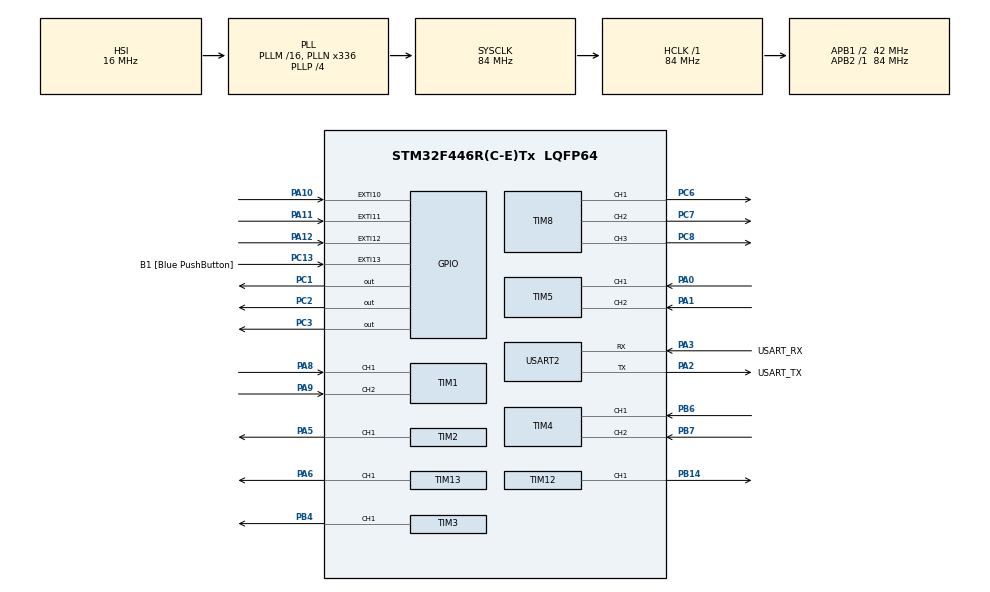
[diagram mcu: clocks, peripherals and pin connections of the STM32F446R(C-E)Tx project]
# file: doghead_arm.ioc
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Dma.Request0=USART2_RX
Dma.Request1=USART2_TX
Dma.USART2_RX.0.Direction=DMA_PERIPH_TO_MEMORY
Dma.USART2_RX.0.FIFOMode=DMA_FIFOMODE_DISABLE
Dma.USART2_RX.0.Instance=DMA1_Stream5
Dma.USART2_RX.0.MemDataAlignment=DMA_MDATAALIGN_BYTE
Dma.USART2_RX.0.MemInc=DMA_MINC_ENABLE
Dma.USART2_RX.0.Mode=DMA_CIRCULAR
Dma.USART2_RX.0.PeriphDataAlignment=DMA_PDATAALIGN_BYTE
Dma.USART2_RX.0.PeriphInc=DMA_PINC_DISABLE
Dma.USART2_RX.0.Priority=DMA_PRIORITY_VERY_HIGH
Dma.USART2_TX.1.Direction=DMA_MEMORY_TO_PERIPH
Dma.USART2_TX.1.FIFOMode=DMA_FIFOMODE_DISABLE
Dma.USART2_TX.1.Instance=DMA1_Stream6
Dma.USART2_TX.1.MemDataAlignment=DMA_MDATAALIGN_BYTE
Dma.USART2_TX.1.MemInc=DMA_MINC_ENABLE
Dma.USART2_TX.1.Mode=DMA_NORMAL
Dma.USART2_TX.1.PeriphDataAlignment=DMA_PDATAALIGN_BYTE
Dma.USART2_TX.1.PeriphInc=DMA_PINC_DISABLE
Dma.USART2_TX.1.Priority=DMA_PRIORITY_VERY_HIGH
FREERTOS.Tasks01=CommTask,24,3072,StartCommTask,Default,NULL,Dynamic,NULL,NULL;ControlTask,32,1024,StartControlTask,Default,NULL,Dynamic,NULL,NULL
FREERTOS.configTOTAL_HEAP_SIZE=49152
FREERTOS.configUSE_NEWLIB_REENTRANT=1
Mcu.Family=STM32F4
Mcu.Name=STM32F446R(C-E)Tx
Mcu.Package=LQFP64
NVIC.DMA1_Stream5_IRQn=true\:6\:0\:true\:false\:true\:true\:false\:true\:true
NVIC.DMA1_Stream6_IRQn=true\:6\:0\:true\:false\:true\:true\:false\:true\:true
NVIC.EXTI15_10_IRQn=true\:5\:0\:false\:false\:true\:true\:true\:true\:true
NVIC.PriorityGroup=NVIC_PRIORITYGROUP_4
NVIC.TIM6_DAC_IRQn=true\:5\:0\:true\:false\:true\:true\:true\:true\:true
NVIC.TIM7_IRQn=true\:15\:0\:false\:false\:true\:false\:false\:true\:true
NVIC.TimeBase=TIM7_IRQn
NVIC.TimeBaseIP=TIM7
NVIC.USART2_IRQn=true\:6\:0\:true\:false\:true\:true\:true\:true\:true
PA0-WKUP.GPIO_PuPd=GPIO_PULLUP
PA0-WKUP.Signal=S_TIM5_CH1
PA1.GPIO_PuPd=GPIO_PULLUP
PA1.Signal=S_TIM5_CH2
PA10.GPIO_ModeDefaultEXTI=GPIO_MODE_IT_RISING_FALLING
PA10.GPIO_PuPd=GPIO_PULLUP
PA10.Signal=GPXTI10
PA11.GPIO_ModeDefaultEXTI=GPIO_MODE_IT_RISING_FALLING
PA11.GPIO_PuPd=GPIO_PULLUP
PA11.Signal=GPXTI11
PA12.GPIO_ModeDefaultEXTI=GPIO_MODE_IT_RISING_FALLING
PA12.GPIO_PuPd=GPIO_PULLUP
PA12.Signal=GPXTI12
PA13.GPIO_Label=TMS
PA13.Mode=Serial_Wire
PA13.Signal=SYS_JTMS-SWDIO
PA14.GPIO_Label=TCK
PA14.Mode=Serial_Wire
PA14.Signal=SYS_JTCK-SWCLK
PA2.GPIO_Label=USART_TX
PA2.Mode=Asynchronous
PA2.Signal=USART2_TX
PA3.GPIO_Label=USART_RX
PA3.Mode=Asynchronous
PA3.Signal=USART2_RX
PA5.Signal=S_TIM2_CH1_ETR
PA6.Signal=S_TIM13_CH1
PA8.GPIO_PuPd=GPIO_PULLUP
PA8.Signal=S_TIM1_CH1
PA9.GPIO_PuPd=GPIO_PULLUP
PA9.Signal=S_TIM1_CH2
PB14.Signal=S_TIM12_CH1
PB3.GPIO_Label=SWO
PB3.Signal=SYS_JTDO-SWO
PB4.Signal=S_TIM3_CH1
PB6.GPIO_PuPd=GPIO_PULLUP
PB6.Signal=S_TIM4_CH1
PB7.GPIO_PuPd=GPIO_PULLUP
PB7.Signal=S_TIM4_CH2
PC1.Signal=GPIO_Output
PC13.GPIO_Label=B1 [Blue PushButton]
PC13.GPIO_ModeDefaultEXTI=GPIO_MODE_IT_FALLING
PC13.Signal=GPXTI13
PC14-OSC32_IN.Mode=LSE-External-Oscillator
PC14-OSC32_IN.Signal=RCC_OSC32_IN
PC15-OSC32_OUT.Mode=LSE-External-Oscillator
PC15-OSC32_OUT.Signal=RCC_OSC32_OUT
PC2.Signal=GPIO_Output
PC3.Signal=GPIO_Output
PC6.Signal=S_TIM8_CH1
PC7.Signal=S_TIM8_CH2
PC8.Signal=S_TIM8_CH3
PH0-OSC_IN.Mode=HSE-External-Oscillator
PH0-OSC_IN.Signal=RCC_OSC_IN
PH1-OSC_OUT.Mode=HSE-External-Oscillator
PH1-OSC_OUT.Signal=RCC_OSC_OUT
ProjectManager.HeapSize=0x200
ProjectManager.StackSize=0x400
ProjectManager.TargetToolchain=STM32CubeIDE
RCC.48MHZClocksFreq_Value=84000000
RCC.AHBFreq_Value=84000000
RCC.APB1CLKDivider=RCC_HCLK_DIV2
RCC.APB1Freq_Value=42000000
RCC.APB1TimFreq_Value=84000000
RCC.APB2Freq_Value=84000000
RCC.APB2TimFreq_Value=84000000
RCC.CortexFreq_Value=84000000
RCC.FLatency-AdvancedSettings=FLASH_LATENCY_2
RCC.HCLKFreq_Value=84000000
RCC.HSE_VALUE=8000000
RCC.HSI_VALUE=16000000
RCC.PLLN=336
RCC.PLLP=RCC_PLLP_DIV4
RCC.SYSCLKFreq_VALUE=84000000
RCC.SYSCLKSource=RCC_SYSCLKSOURCE_PLLCLK
RCC.USBFreq_Value=168000000
RCC.VCOOutputFreq_Value=336000000
SH.S_TIM12_CH1.0=TIM12_CH1,PWM Generation1 CH1
SH.S_TIM13_CH1.0=TIM13_CH1,PWM Generation1 CH1
SH.S_TIM1_CH1.0=TIM1_CH1,Encoder_Interface
SH.S_TIM1_CH2.0=TIM1_CH2,Encoder_Interface
SH.S_TIM2_CH1_ETR.0=TIM2_CH1,PWM Generation1 CH1
SH.S_TIM3_CH1.0=TIM3_CH1,PWM Generation1 CH1
SH.S_TIM4_CH1.0=TIM4_CH1,Encoder_Interface
SH.S_TIM4_CH2.0=TIM4_CH2,Encoder_Interface
SH.S_TIM5_CH1.0=TIM5_CH1,Encoder_Interface
SH.S_TIM5_CH2.0=TIM5_CH2,Encoder_Interface
SH.S_TIM8_CH1.0=TIM8_CH1,PWM Generation1 CH1
SH.S_TIM8_CH2.0=TIM8_CH2,PWM Generation2 CH2
SH.S_TIM8_CH3.0=TIM8_CH3,PWM Generation3 CH3
TIM1.EncoderMode=TIM_ENCODERMODE_TI12
TIM1.IC1Filter=7
TIM1.IC2Filter=7
TIM12.Channel-PWM\ Generation1\ CH1=TIM_CHANNEL_1
TIM13.Channel=TIM_CHANNEL_1
TIM2.AutoReloadPreload=TIM_AUTORELOAD_PRELOAD_ENABLE
TIM2.Channel-PWM\ Generation1\ CH1=TIM_CHANNEL_1
TIM3.AutoReloadPreload=TIM_AUTORELOAD_PRELOAD_ENABLE
TIM3.Channel-PWM\ Generation1\ CH1=TIM_CHANNEL_1
TIM4.EncoderMode=TIM_ENCODERMODE_TI12
TIM4.IC1Filter=7
TIM4.IC2Filter=7
TIM5.EncoderMode=TIM_ENCODERMODE_TI12
TIM5.IC1Filter=7
TIM5.IC2Filter=7
TIM6.Period=999
TIM6.Prescaler=83
TIM8.Channel-PWM\ Generation1\ CH1=TIM_CHANNEL_1
TIM8.Channel-PWM\ Generation2\ CH2=TIM_CHANNEL_2
TIM8.Channel-PWM\ Generation3\ CH3=TIM_CHANNEL_3
USART2.VirtualMode=VM_ASYNC
VP_FREERTOS_VS_CMSIS_V2.Mode=CMSIS_V2
VP_SYS_VS_tim7.Mode=TIM7
VP_TIM13_VS_ClockSourceINT.Mode=Enable_Timer
VP_TIM6_VS_ClockSourceINT.Mode=Enable_Timer
board=NUCLEO-F446RE

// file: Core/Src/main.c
/* USER CODE BEGIN Header */
/**
  ******************************************************************************
  * @file           : main.c
  * @brief          : Main program body
  ******************************************************************************
  * @attention
  *
  * Copyright (c) 2025 STMicroelectronics.
  * All rights reserved.
  *
  * This software is licensed under terms that can be found in the LICENSE file
  * in the root directory of this software component.
  * If no LICENSE file comes with this software, it is provided AS-IS.
  *
  ******************************************************************************
  */
/* USER CODE END Header */
#include "main.h"
#include "cmsis_os.h"

/* USER CODE BEGIN Includes */
#include "mainpp.h"
#include "robot_config.h"
#include "hardware_io.h"
//#include <rcl/rcl.h>
//#include <rcl/error_handling.h>
//#include <rclc/rclc.h>
//#include <rclc/executor.h>
//#include <uxr/client/transport.h>
//#include <rmw_microxrcedds_c/config.h>
//#include <rmw_microros/rmw_microros.h>
/* USER CODE END Includes */

TIM_HandleTypeDef htim1;
TIM_HandleTypeDef htim2;
TIM_HandleTypeDef htim3;
TIM_HandleTypeDef htim4;
TIM_HandleTypeDef htim5;
TIM_HandleTypeDef htim6;
TIM_HandleTypeDef htim8;
TIM_HandleTypeDef htim12;
TIM_HandleTypeDef htim13;

UART_HandleTypeDef huart2;
DMA_HandleTypeDef hdma_usart2_rx;
DMA_HandleTypeDef hdma_usart2_tx;

/* Definitions for defaultTask */
osThreadId_t defaultTaskHandle;
const osThreadAttr_t defaultTask_attributes = {
  .name = "defaultTask",
  .stack_size = 512 * 4,
  .priority = (osPriority_t) osPriorityNormal,
};
/* USER CODE BEGIN PV */
// 所有的控制變數已經移動到 robot_arm_core.cpp 與 mainpp.h

// [Task Handle] 控制任務句柄（供 TIM6 中斷使用）
TaskHandle_t xControlTaskHandle = NULL;
/* USER CODE END PV */

void SystemClock_Config(void);
static void MX_GPIO_Init(void);
static void MX_DMA_Init(void);
static void MX_USART2_UART_Init(void);
static void MX_TIM1_Init(void);
static void MX_TIM2_Init(void);
static void MX_TIM3_Init(void);
static void MX_TIM4_Init(void);
static void MX_TIM6_Init(void);
static void MX_TIM5_Init(void);
static void MX_TIM8_Init(void);
static void MX_TIM12_Init(void);
static void MX_TIM13_Init(void);
void StartDefaultTask(void *argument);

/* USER CODE BEGIN PFP */
#include "nidec_motor_driver.h"
void MX_FREERTOS_Init(void);
/* USER CODE END PFP */

/* USER CODE BEGIN 0 */
#include "runtime_monitor.h"
/* USER CODE END 0 */

int main(void)
{

  /* MCU Configuration--------------------------------------------------------*/

  /* Reset of all peripherals, Initializes the Flash interface and the Systick. */
																																				  HAL_Init();

  /* Configure the system clock */
  SystemClock_Config();

  /* USER CODE BEGIN SysInit */
  RuntimeMonitor_Init();
  /* USER CODE END SysInit */

  /* Initialize all configured peripherals */
  MX_GPIO_Init();
  MX_DMA_Init();
  MX_USART2_UART_Init();
  MX_TIM1_Init();
  MX_TIM2_Init();
  MX_TIM3_Init();
  MX_TIM4_Init();
  MX_TIM6_Init();
  MX_TIM5_Init();
  MX_TIM8_Init();
  MX_TIM12_Init();
  MX_TIM13_Init();
  /* USER CODE BEGIN 2 */
    Robot_Init();
    // 模式切換統一使用 test_mode_selection 變數控制
  /* USER CODE END 2 */

  /* Init scheduler */
  osKernelInitialize();

  /* Create the thread(s) */
  /* creation of defaultTask */
  defaultTaskHandle = osThreadNew(StartDefaultTask, NULL, &defaultTask_attributes);
  if (defaultTaskHandle == NULL) {
    Error_Handler();
  }

  /* USER CODE BEGIN RTOS_THREADS */
  /* add threads, ... */
  MX_FREERTOS_Init();  // 建立自訂的控制任務和通訊任務
  /* USER CODE END RTOS_THREADS */

  /* Start scheduler */
  osKernelStart();

  /* We should never get here as control is now taken by the scheduler */

  /* Infinite loop */
  while (1)
  {

    /* USER CODE BEGIN 3 */
    // 注意: FreeRTOS 啟動後 (osKernelStart) 不會執行這裡
    // 所有控制邏輯應放在 FreeRTOS 任務中
  }
  /* USER CODE END 3 */
}

void SystemClock_Config(void)
{
  RCC_OscInitTypeDef RCC_OscInitStruct = {0};
  RCC_ClkInitTypeDef RCC_ClkInitStruct = {0};

  /** Configure the main internal regulator output voltage
  */
  __HAL_RCC_PWR_CLK_ENABLE();
  __HAL_PWR_VOLTAGESCALING_CONFIG(PWR_REGULATOR_VOLTAGE_SCALE3);

  /** Initializes the RCC Oscillators according to the specified parameters
  * in the RCC_OscInitTypeDef structure.
  */
  RCC_OscInitStruct.OscillatorType = RCC_OSCILLATORTYPE_HSI;
  RCC_OscInitStruct.HSIState = RCC_HSI_ON;
  RCC_OscInitStruct.HSICalibrationValue = RCC_HSICALIBRATION_DEFAULT;
  RCC_OscInitStruct.PLL.PLLState = RCC_PLL_ON;
  RCC_OscInitStruct.PLL.PLLSource = RCC_PLLSOURCE_HSI;
  RCC_OscInitStruct.PLL.PLLM = 16;
  RCC_OscInitStruct.PLL.PLLN = 336;
  RCC_OscInitStruct.PLL.PLLP = RCC_PLLP_DIV4;
  RCC_OscInitStruct.PLL.PLLQ = 2;
  RCC_OscInitStruct.PLL.PLLR = 2;
  if (HAL_RCC_OscConfig(&RCC_OscInitStruct) != HAL_OK)
  {
    Error_Handler();
  }

  /** Initializes the CPU, AHB and APB buses clocks
  */
  RCC_ClkInitStruct.ClockType = RCC_CLOCKTYPE_HCLK|RCC_CLOCKTYPE_SYSCLK
                              |RCC_CLOCKTYPE_PCLK1|RCC_CLOCKTYPE_PCLK2;
  RCC_ClkInitStruct.SYSCLKSource = RCC_SYSCLKSOURCE_PLLCLK;
  RCC_ClkInitStruct.AHBCLKDivider = RCC_SYSCLK_DIV1;
  RCC_ClkInitStruct.APB1CLKDivider = RCC_HCLK_DIV2;
  RCC_ClkInitStruct.APB2CLKDivider = RCC_HCLK_DIV1;

  if (HAL_RCC_ClockConfig(&RCC_ClkInitStruct, FLASH_LATENCY_2) != HAL_OK)
  {
    Error_Handler();
  }
}

static void MX_TIM1_Init(void)
{

  TIM_Encoder_InitTypeDef sConfig = {0};
  TIM_MasterConfigTypeDef sMasterConfig = {0};

  htim1.Instance = TIM1;
  htim1.Init.Prescaler = 0;
  htim1.Init.CounterMode = TIM_COUNTERMODE_UP;
  htim1.Init.Period = 65535;
  htim1.Init.ClockDivision = TIM_CLOCKDIVISION_DIV1;
  htim1.Init.RepetitionCounter = 0;
  htim1.Init.AutoReloadPreload = TIM_AUTORELOAD_PRELOAD_DISABLE;
  sConfig.EncoderMode = TIM_ENCODERMODE_TI12;
  sConfig.IC1Polarity = TIM_ICPOLARITY_RISING;
  sConfig.IC1Selection = TIM_ICSELECTION_DIRECTTI;
  sConfig.IC1Prescaler = TIM_ICPSC_DIV1;
  sConfig.IC1Filter = 7;
  sConfig.IC2Polarity = TIM_ICPOLARITY_RISING;
  sConfig.IC2Selection = TIM_ICSELECTION_DIRECTTI;
  sConfig.IC2Prescaler = TIM_ICPSC_DIV1;
  sConfig.IC2Filter = 7;
  if (HAL_TIM_Encoder_Init(&htim1, &sConfig) != HAL_OK)
  {
    Error_Handler();
  }
  sMasterConfig.MasterOutputTrigger = TIM_TRGO_RESET;
  sMasterConfig.MasterSlaveMode = TIM_MASTERSLAVEMODE_DISABLE;
  if (HAL_TIMEx_MasterConfigSynchronization(&htim1, &sMasterConfig) != HAL_OK)
  {
    Error_Handler();
  }

}

static void MX_TIM2_Init(void)
{

  TIM_MasterConfigTypeDef sMasterConfig = {0};
  TIM_OC_InitTypeDef sConfigOC = {0};

  htim2.Instance = TIM2;
  htim2.Init.Prescaler = 0;
  htim2.Init.CounterMode = TIM_COUNTERMODE_UP;
  htim2.Init.Period = 4294967295;
  htim2.Init.ClockDivision = TIM_CLOCKDIVISION_DIV1;
  htim2.Init.AutoReloadPreload = TIM_AUTORELOAD_PRELOAD_ENABLE;
  if (HAL_TIM_PWM_Init(&htim2) != HAL_OK)
  {
    Error_Handler();
  }
  sMasterConfig.MasterOutputTrigger = TIM_TRGO_RESET;
  sMasterConfig.MasterSlaveMode = TIM_MASTERSLAVEMODE_DISABLE;
  if (HAL_TIMEx_MasterConfigSynchronization(&htim2, &sMasterConfig) != HAL_OK)
  {
    Error_Handler();
  }
  sConfigOC.OCMode = TIM_OCMODE_PWM1;
  sConfigOC.Pulse = 0;
  sConfigOC.OCPolarity = TIM_OCPOLARITY_HIGH;
  sConfigOC.OCFastMode = TIM_OCFAST_DISABLE;
  if (HAL_TIM_PWM_ConfigChannel(&htim2, &sConfigOC, TIM_CHANNEL_1) != HAL_OK)
  {
    Error_Handler();
  }
  HAL_TIM_MspPostInit(&htim2);

}

static void MX_TIM3_Init(void)
{

  TIM_MasterConfigTypeDef sMasterConfig = {0};
  TIM_OC_InitTypeDef sConfigOC = {0};

  htim3.Instance = TIM3;
  htim3.Init.Prescaler = 0;
  htim3.Init.CounterMode = TIM_COUNTERMODE_UP;
  htim3.Init.Period = 65535;
  htim3.Init.ClockDivision = TIM_CLOCKDIVISION_DIV1;
  htim3.Init.AutoReloadPreload = TIM_AUTORELOAD_PRELOAD_ENABLE;
  if (HAL_TIM_PWM_Init(&htim3) != HAL_OK)
  {
    Error_Handler();
  }
  sMasterConfig.MasterOutputTrigger = TIM_TRGO_RESET;
  sMasterConfig.MasterSlaveMode = TIM_MASTERSLAVEMODE_DISABLE;
  if (HAL_TIMEx_MasterConfigSynchronization(&htim3, &sMasterConfig) != HAL_OK)
  {
    Error_Handler();
  }
  sConfigOC.OCMode = TIM_OCMODE_PWM1;
  sConfigOC.Pulse = 0;
  sConfigOC.OCPolarity = TIM_OCPOLARITY_HIGH;
  sConfigOC.OCFastMode = TIM_OCFAST_DISABLE;
  if (HAL_TIM_PWM_ConfigChannel(&htim3, &sConfigOC, TIM_CHANNEL_1) != HAL_OK)
  {
    Error_Handler();
  }
  HAL_TIM_MspPostInit(&htim3);

}

static void MX_TIM4_Init(void)
{

  TIM_Encoder_InitTypeDef sConfig = {0};
  TIM_MasterConfigTypeDef sMasterConfig = {0};

  htim4.Instance = TIM4;
  htim4.Init.Prescaler = 0;
  htim4.Init.CounterMode = TIM_COUNTERMODE_UP;
  htim4.Init.Period = 65535;
  htim4.Init.ClockDivision = TIM_CLOCKDIVISION_DIV1;
  htim4.Init.AutoReloadPreload = TIM_AUTORELOAD_PRELOAD_DISABLE;
  sConfig.EncoderMode = TIM_ENCODERMODE_TI12;
  sConfig.IC1Polarity = TIM_ICPOLARITY_RISING;
  sConfig.IC1Selection = TIM_ICSELECTION_DIRECTTI;
  sConfig.IC1Prescaler = TIM_ICPSC_DIV1;
  sConfig.IC1Filter = 7;
  sConfig.IC2Polarity = TIM_ICPOLARITY_RISING;
  sConfig.IC2Selection = TIM_ICSELECTION_DIRECTTI;
  sConfig.IC2Prescaler = TIM_ICPSC_DIV1;
  sConfig.IC2Filter = 7;
  if (HAL_TIM_Encoder_Init(&htim4, &sConfig) != HAL_OK)
  {
    Error_Handler();
  }
  sMasterConfig.MasterOutputTrigger = TIM_TRGO_RESET;
  sMasterConfig.MasterSlaveMode = TIM_MASTERSLAVEMODE_DISABLE;
  if (HAL_TIMEx_MasterConfigSynchronization(&htim4, &sMasterConfig) != HAL_OK)
  {
    Error_Handler();
  }

}

static void MX_TIM5_Init(void)
{

  TIM_Encoder_InitTypeDef sConfig = {0};
  TIM_MasterConfigTypeDef sMasterConfig = {0};

  htim5.Instance = TIM5;
  htim5.Init.Prescaler = 0;
  htim5.Init.CounterMode = TIM_COUNTERMODE_UP;
  htim5.Init.Period = 4294967295;
  htim5.Init.ClockDivision = TIM_CLOCKDIVISION_DIV1;
  htim5.Init.AutoReloadPreload = TIM_AUTORELOAD_PRELOAD_DISABLE;
  sConfig.EncoderMode = TIM_ENCODERMODE_TI12;
  sConfig.IC1Polarity = TIM_ICPOLARITY_RISING;
  sConfig.IC1Selection = TIM_ICSELECTION_DIRECTTI;
  sConfig.IC1Prescaler = TIM_ICPSC_DIV1;
  sConfig.IC1Filter = 7;
  sConfig.IC2Polarity = TIM_ICPOLARITY_RISING;
  sConfig.IC2Selection = TIM_ICSELECTION_DIRECTTI;
  sConfig.IC2Prescaler = TIM_ICPSC_DIV1;
  sConfig.IC2Filter = 7;
  if (HAL_TIM_Encoder_Init(&htim5, &sConfig) != HAL_OK)
  {
    Error_Handler();
  }
  sMasterConfig.MasterOutputTrigger = TIM_TRGO_RESET;
  sMasterConfig.MasterSlaveMode = TIM_MASTERSLAVEMODE_DISABLE;
  if (HAL_TIMEx_MasterConfigSynchronization(&htim5, &sMasterConfig) != HAL_OK)
  {
    Error_Handler();
  }

}

static void MX_TIM6_Init(void)
{

  TIM_MasterConfigTypeDef sMasterConfig = {0};

  htim6.Instance = TIM6;
  htim6.Init.Prescaler = 83;
  htim6.Init.CounterMode = TIM_COUNTERMODE_UP;
  htim6.Init.Period = 999;
  htim6.Init.AutoReloadPreload = TIM_AUTORELOAD_PRELOAD_DISABLE;
  if (HAL_TIM_Base_Init(&htim6) != HAL_OK)
  {
    Error_Handler();
  }
  sMasterConfig.MasterOutputTrigger = TIM_TRGO_RESET;
  sMasterConfig.MasterSlaveMode = TIM_MASTERSLAVEMODE_DISABLE;
  if (HAL_TIMEx_MasterConfigSynchronization(&htim6, &sMasterConfig) != HAL_OK)
  {
    Error_Handler();
  }

}

static void MX_TIM8_Init(void)
{

  TIM_MasterConfigTypeDef sMasterConfig = {0};
  TIM_OC_InitTypeDef sConfigOC = {0};
  TIM_BreakDeadTimeConfigTypeDef sBreakDeadTimeConfig = {0};

  htim8.Instance = TIM8;
  htim8.Init.Prescaler = 0;
  htim8.Init.CounterMode = TIM_COUNTERMODE_UP;
  htim8.Init.Period = 65535;
  htim8.Init.ClockDivision = TIM_CLOCKDIVISION_DIV1;
  htim8.Init.RepetitionCounter = 0;
  htim8.Init.AutoReloadPreload = TIM_AUTORELOAD_PRELOAD_DISABLE;
  if (HAL_TIM_PWM_Init(&htim8) != HAL_OK)
  {
    Error_Handler();
  }
  sMasterConfig.MasterOutputTrigger = TIM_TRGO_RESET;
  sMasterConfig.MasterSlaveMode = TIM_MASTERSLAVEMODE_DISABLE;
  if (HAL_TIMEx_MasterConfigSynchronization(&htim8, &sMasterConfig) != HAL_OK)
  {
    Error_Handler();
  }
  sConfigOC.OCMode = TIM_OCMODE_PWM1;
  sConfigOC.Pulse = 0;
  sConfigOC.OCPolarity = TIM_OCPOLARITY_HIGH;
  sConfigOC.OCNPolarity = TIM_OCNPOLARITY_HIGH;
  sConfigOC.OCFastMode = TIM_OCFAST_DISABLE;
  sConfigOC.OCIdleState = TIM_OCIDLESTATE_RESET;
  sConfigOC.OCNIdleState = TIM_OCNIDLESTATE_RESET;
  if (HAL_TIM_PWM_ConfigChannel(&htim8, &sConfigOC, TIM_CHANNEL_1) != HAL_OK)
  {
    Error_Handler();
  }
  if (HAL_TIM_PWM_ConfigChannel(&htim8, &sConfigOC, TIM_CHANNEL_2) != HAL_OK)
  {
    Error_Handler();
  }
  if (HAL_TIM_PWM_ConfigChannel(&htim8, &sConfigOC, TIM_CHANNEL_3) != HAL_OK)
  {
    Error_Handler();
  }
  sBreakDeadTimeConfig.OffStateRunMode = TIM_OSSR_DISABLE;
  sBreakDeadTimeConfig.OffStateIDLEMode = TIM_OSSI_DISABLE;
  sBreakDeadTimeConfig.LockLevel = TIM_LOCKLEVEL_OFF;
  sBreakDeadTimeConfig.DeadTime = 0;
  sBreakDeadTimeConfig.BreakState = TIM_BREAK_DISABLE;
  sBreakDeadTimeConfig.BreakPolarity = TIM_BREAKPOLARITY_HIGH;
  sBreakDeadTimeConfig.AutomaticOutput = TIM_AUTOMATICOUTPUT_DISABLE;
  if (HAL_TIMEx_ConfigBreakDeadTime(&htim8, &sBreakDeadTimeConfig) != HAL_OK)
  {
    Error_Handler();
  }
  HAL_TIM_MspPostInit(&htim8);

}

static void MX_TIM12_Init(void)
{

  TIM_OC_InitTypeDef sConfigOC = {0};

  htim12.Instance = TIM12;
  htim12.Init.Prescaler = 0;
  htim12.Init.CounterMode = TIM_COUNTERMODE_UP;
  htim12.Init.Period = 65535;
  htim12.Init.ClockDivision = TIM_CLOCKDIVISION_DIV1;
  htim12.Init.AutoReloadPreload = TIM_AUTORELOAD_PRELOAD_DISABLE;
  if (HAL_TIM_PWM_Init(&htim12) != HAL_OK)
  {
    Error_Handler();
  }
  sConfigOC.OCMode = TIM_OCMODE_PWM1;
  sConfigOC.Pulse = 0;
  sConfigOC.OCPolarity = TIM_OCPOLARITY_HIGH;
  sConfigOC.OCFastMode = TIM_OCFAST_DISABLE;
  if (HAL_TIM_PWM_ConfigChannel(&htim12, &sConfigOC, TIM_CHANNEL_1) != HAL_OK)
  {
    Error_Handler();
  }
  HAL_TIM_MspPostInit(&htim12);

}

static void MX_TIM13_Init(void)
{

  TIM_OC_InitTypeDef sConfigOC = {0};

  htim13.Instance = TIM13;
  htim13.Init.Prescaler = 0;
  htim13.Init.CounterMode = TIM_COUNTERMODE_UP;
  htim13.Init.Period = 65535;
  htim13.Init.ClockDivision = TIM_CLOCKDIVISION_DIV1;
  htim13.Init.AutoReloadPreload = TIM_AUTORELOAD_PRELOAD_DISABLE;
  if (HAL_TIM_Base_Init(&htim13) != HAL_OK)
  {
    Error_Handler();
  }
  if (HAL_TIM_PWM_Init(&htim13) != HAL_OK)
  {
    Error_Handler();
  }
  sConfigOC.OCMode = TIM_OCMODE_PWM1;
  sConfigOC.Pulse = 0;
  sConfigOC.OCPolarity = TIM_OCPOLARITY_HIGH;
  sConfigOC.OCFastMode = TIM_OCFAST_DISABLE;
  if (HAL_TIM_PWM_ConfigChannel(&htim13, &sConfigOC, TIM_CHANNEL_1) != HAL_OK)
  {
    Error_Handler();
  }
  HAL_TIM_MspPostInit(&htim13);

}

static void MX_USART2_UART_Init(void)
{

  huart2.Instance = USART2;
  huart2.Init.BaudRate = MICROROS_BAUD_RATE;
  huart2.Init.WordLength = UART_WORDLENGTH_8B;
  huart2.Init.StopBits = UART_STOPBITS_1;
  huart2.Init.Parity = UART_PARITY_NONE;
  huart2.Init.Mode = UART_MODE_TX_RX;
  huart2.Init.HwFlowCtl = UART_HWCONTROL_NONE;
  huart2.Init.OverSampling = UART_OVERSAMPLING_16;
  if (HAL_UART_Init(&huart2) != HAL_OK)
  {
    Error_Handler();
  }

}

static void MX_GPIO_Init(void)
{
  GPIO_InitTypeDef GPIO_InitStruct = {0};

  /* GPIO Ports Clock Enable */
  __HAL_RCC_GPIOC_CLK_ENABLE();
  __HAL_RCC_GPIOH_CLK_ENABLE();
  __HAL_RCC_GPIOA_CLK_ENABLE();
  __HAL_RCC_GPIOB_CLK_ENABLE();

  /*Configure GPIO pin Output Level */
  HAL_GPIO_WritePin(GPIOC, GPIO_PIN_1|GPIO_PIN_2|GPIO_PIN_3|GPIO_PIN_4
                          |GPIO_PIN_5, GPIO_PIN_RESET);

  /*Configure GPIO pin : B1_Pin */
  GPIO_InitStruct.Pin = B1_Pin;
  GPIO_InitStruct.Mode = GPIO_MODE_IT_FALLING;
  GPIO_InitStruct.Pull = GPIO_NOPULL;
  HAL_GPIO_Init(B1_GPIO_Port, &GPIO_InitStruct);

  /*Configure GPIO pins : PC1 PC2 PC3 PC4
                           PC5 */
  GPIO_InitStruct.Pin = GPIO_PIN_1|GPIO_PIN_2|GPIO_PIN_3|GPIO_PIN_4
                          |GPIO_PIN_5;
  GPIO_InitStruct.Mode = GPIO_MODE_OUTPUT_PP;
  GPIO_InitStruct.Pull = GPIO_NOPULL;
  GPIO_InitStruct.Speed = GPIO_SPEED_FREQ_LOW;
  HAL_GPIO_Init(GPIOC, &GPIO_InitStruct);

  /*Configure GPIO pins : PA10 PA11 PA12 */
  GPIO_InitStruct.Pin = GPIO_PIN_10|GPIO_PIN_11|GPIO_PIN_12;
  GPIO_InitStruct.Mode = GPIO_MODE_IT_RISING_FALLING;
  GPIO_InitStruct.Pull = GPIO_PULLUP;
  HAL_GPIO_Init(GPIOA, &GPIO_InitStruct);

  /* EXTI interrupt init*/
  HAL_NVIC_SetPriority(EXTI15_10_IRQn, 5, 0);
  HAL_NVIC_EnableIRQ(EXTI15_10_IRQn);

}

/* USER CODE BEGIN 4 */
int __io_putchar(int ch)
{
  HAL_UART_Transmit(&huart2, (uint8_t *)&ch, 1, HAL_MAX_DELAY);
  return ch;
}
/**
  * Enable DMA controller clock
  */
static void MX_DMA_Init(void)
{
  /* DMA controller clock enable */
  __HAL_RCC_DMA1_CLK_ENABLE();

  /* DMA interrupt init */
  /* DMA1_Stream5_IRQn interrupt configuration */
  HAL_NVIC_SetPriority(DMA1_Stream5_IRQn, 6, 0);
  HAL_NVIC_EnableIRQ(DMA1_Stream5_IRQn);
  /* DMA1_Stream6_IRQn interrupt configuration */
  HAL_NVIC_SetPriority(DMA1_Stream6_IRQn, 6, 0);
  HAL_NVIC_EnableIRQ(DMA1_Stream6_IRQn);
}

void HAL_GPIO_EXTI_Callback(uint16_t GPIO_Pin)
{
  HW_OnExtInterrupt(GPIO_Pin);
}

/* USER CODE END 4 */

void StartDefaultTask(void *argument)
{
  /* USER CODE BEGIN 5 */
  /* Infinite loop */
  for(;;)
  {
    osDelay(1000);
  }
  /* USER CODE END 5 */
}

void HAL_TIM_PeriodElapsedCallback(TIM_HandleTypeDef *htim)
{
  if (htim->Instance == TIM7)
  {
    HAL_IncTick();
  }
  /* USER CODE BEGIN Callback 1 */
  // 合併來自 stm32f4xx_it.c 的 TIM6 處理邏輯
  if (htim->Instance == TIM6) {
    BaseType_t xHigherPriorityTaskWoken = pdFALSE;

    // 發送通知到控制任務（從中斷安全版本）
    if (xControlTaskHandle != NULL) {
      vTaskNotifyGiveFromISR(xControlTaskHandle, &xHigherPriorityTaskWoken);
    }

    // 如果喚醒了更高優先級任務，請求上下文切換
    portYIELD_FROM_ISR(xHigherPriorityTaskWoken);
  }
  /* USER CODE END Callback 1 */
}

void Error_Handler(void)
{
  __disable_irq();
  while (1)
  {
  }
}

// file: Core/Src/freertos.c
/* USER CODE BEGIN Header */
/**
  ******************************************************************************
  * File Name          : freertos.c
  * Description        : Code for freertos applications
  * Note               : Core/Src/freertos.c is the active FreeRTOS initialization
  *                      and 1 kHz ControlTask/CommTask implementation owner.
  ******************************************************************************
  */
/* USER CODE END Header */

#include "FreeRTOS.h"
#include "task.h"
#include "main.h"
#include "cmsis_os.h"

/* USER CODE BEGIN Includes */
#include "microros_app.h"
#include "mainpp.h"
#include "robot_interface.h"
#include "safety_manager.h"
#include "runtime_monitor.h"
#include "freertos_runtime.h"
/* USER CODE END Includes */

/* USER CODE BEGIN Variables */
extern TaskHandle_t xControlTaskHandle;

static osThreadId_t commTaskHandle;
const osThreadAttr_t commTask_attributes = {
  .name = "commTask",
  .stack_size = 3000 * 4,
  .priority = (osPriority_t) osPriorityHigh,
};

static osThreadId_t controlTaskHandle;
static TaskHandle_t g_commTaskHandle = NULL;
static TaskHandle_t g_controlTaskHandle = NULL;
const osThreadAttr_t controlTask_attributes = {
  .name = "controlTask",
  .stack_size = 2000 * 4,
  .priority = (osPriority_t) osPriorityRealtime,
};
/* USER CODE END Variables */

/* USER CODE BEGIN FunctionPrototypes */
void StartCommTask(void *argument);
void StartControlTask(void *argument);
/* USER CODE END FunctionPrototypes */

/* USER CODE BEGIN Application */
void StartCommTask(void *argument) {
    (void)argument;
    // Default ping-only micro-ROS transport bringup (safe against pre-main HardFaults)
    MicroROS_Init();

    TickType_t last_state_pub = xTaskGetTickCount();
    TickType_t last_diag_pub = xTaskGetTickCount();

    for (;;) {
        // MicroROS_Spin handles rmw_uros_ping_agent XRCE session verification (and RCL entity creation if enabled)
        MicroROS_Spin();
        TickType_t now = xTaskGetTickCount();

        // 50 Hz McuState & /joint_states publication (every 20 ms)
        const TickType_t state_period = pdMS_TO_TICKS(20);
        if ((now - last_state_pub) >= state_period) {
            RobotTelemetry_t telem;
            RobotInterface_GetTelemetry(&telem);
            MicroROS_PublishMcuState(&telem);
            MicroROS_PublishJointStates(&telem);

            last_state_pub += state_period;
            if ((now - last_state_pub) >= state_period) {
                last_state_pub = now;
            }
        }

        // 1 Hz McuDiagnostics publication (every 1000 ms)
        if ((now - last_diag_pub) >= pdMS_TO_TICKS(1000)) {
            last_diag_pub = now;
            RobotDiagnostics_t diag;
            RobotInterface_GetDiagnostics(&diag);
            MicroROS_PublishMcuDiagnostics(&diag);
        }

        vTaskDelay(pdMS_TO_TICKS(1));
    }
}

void StartControlTask(void *argument) {
    (void)argument;
    xControlTaskHandle = xTaskGetCurrentTaskHandle();
    TickType_t xLastWakeTime = xTaskGetTickCount();
    const TickType_t xFrequency = pdMS_TO_TICKS(1);

    for (;;) {
        vTaskDelayUntil(&xLastWakeTime, xFrequency);
        uint32_t start_cycles = DWT->CYCCNT;
        Robot_ControlTask_Tick(0.001f);
        uint32_t cycles = DWT->CYCCNT - start_cycles;
        const bool missed = cycles >= (SystemCoreClock / 1000U);
        RuntimeMonitor_RecordSample(cycles, missed);
        if (RuntimeMonitor_GetConsecutiveMisses() >= 3U) {
            RobotSafety_TriggerFault(ROBOT_FAULT_DEADLINE_MISS);
        }
    }
}

void MX_FREERTOS_Init(void) {
    commTaskHandle = osThreadNew(StartCommTask, NULL, &commTask_attributes);
    if (commTaskHandle == NULL) {
        Error_Handler();
        return;
    }
    g_commTaskHandle = (TaskHandle_t)commTaskHandle;
    controlTaskHandle = osThreadNew(StartControlTask, NULL, &controlTask_attributes);
    if (controlTaskHandle == NULL) {
        Error_Handler();
        return;
    }
    g_controlTaskHandle = (TaskHandle_t)controlTaskHandle;
}

uint32_t Robot_GetControlStackHighWatermark(void) {
    return g_controlTaskHandle == NULL ? 0U :
        (uint32_t)uxTaskGetStackHighWaterMark(g_controlTaskHandle);
}

uint32_t Robot_GetCommStackHighWatermark(void) {
    return g_commTaskHandle == NULL ? 0U :
        (uint32_t)uxTaskGetStackHighWaterMark(g_commTaskHandle);
}

/**
 * @brief FreeRTOS Stack Overflow Hook function
 * @note Triggered when configCHECK_FOR_STACK_OVERFLOW > 0 and stack overflow is detected
 */
void vApplicationStackOverflowHook(TaskHandle_t xTask, char *pcTaskName) {
    (void)xTask;
    (void)pcTaskName;
    RobotSafety_TriggerFault(ROBOT_FAULT_DEADLINE_MISS);
    taskDISABLE_INTERRUPTS();
    for (;;) {
    }
}
/* USER CODE END Application */
